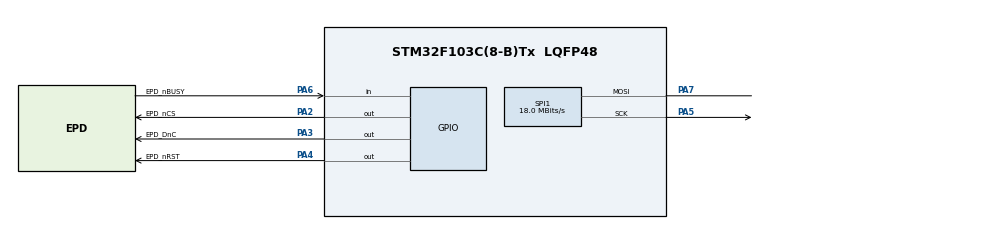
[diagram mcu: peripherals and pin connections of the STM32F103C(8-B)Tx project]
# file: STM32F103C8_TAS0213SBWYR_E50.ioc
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Mcu.Family=STM32F1
Mcu.Name=STM32F103C(8-B)Tx
Mcu.Package=LQFP48
NVIC.PriorityGroup=NVIC_PRIORITYGROUP_4
PA13.Mode=Serial_Wire
PA13.Signal=SYS_JTMS-SWDIO
PA14.Mode=Serial_Wire
PA14.Signal=SYS_JTCK-SWCLK
PA2.GPIO_Label=EPD_nCS
PA2.Signal=GPIO_Output
PA3.GPIO_Label=EPD_DnC
PA3.Signal=GPIO_Output
PA4.GPIO_Label=EPD_nRST
PA4.Signal=GPIO_Output
PA5.Mode=Simplex_Bidirectional_Master
PA5.Signal=SPI1_SCK
PA6.GPIO_Label=EPD_nBUSY
PA6.Signal=GPIO_Input
PA7.Mode=Simplex_Bidirectional_Master
PA7.Signal=SPI1_MOSI
PC14-OSC32_IN.Mode=LSE-External-Oscillator
PC14-OSC32_IN.Signal=RCC_OSC32_IN
PC15-OSC32_OUT.Mode=LSE-External-Oscillator
PC15-OSC32_OUT.Signal=RCC_OSC32_OUT
PD0-OSC_IN.Mode=HSE-External-Oscillator
PD0-OSC_IN.Signal=RCC_OSC_IN
PD1-OSC_OUT.Mode=HSE-External-Oscillator
PD1-OSC_OUT.Signal=RCC_OSC_OUT
ProjectManager.HeapSize=0x200
ProjectManager.StackSize=0x400
ProjectManager.TargetToolchain=CMake
RCC.AHBFreq_Value=72000000
RCC.APB1CLKDivider=RCC_HCLK_DIV2
RCC.APB1Freq_Value=36000000
RCC.APB1TimFreq_Value=72000000
RCC.APB2Freq_Value=72000000
RCC.APB2TimFreq_Value=72000000
RCC.HCLKFreq_Value=72000000
RCC.PLLMUL=RCC_PLL_MUL9
RCC.PLLSourceVirtual=RCC_PLLSOURCE_HSE
RCC.SYSCLKFreq_VALUE=72000000
RCC.SYSCLKSource=RCC_SYSCLKSOURCE_PLLCLK
RCC.USBFreq_Value=48000000
RCC.USBPrescaler=RCC_USBCLKSOURCE_PLL_DIV1_5
SPI1.BaudRatePrescaler=SPI_BAUDRATEPRESCALER_4
SPI1.CalculateBaudRate=18.0 MBits/s
SPI1.Direction=SPI_DIRECTION_1LINE
SPI1.Mode=SPI_MODE_MASTER
SPI1.VirtualType=VM_MASTER
board=custom

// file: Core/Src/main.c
/* USER CODE BEGIN Header */
/**
  ******************************************************************************
  * @file           : main.c
  * @brief          : Main program body
  ******************************************************************************
  * @attention
  *
  * Copyright (c) 2025 STMicroelectronics.
  * All rights reserved.
  *
  * This software is licensed under terms that can be found in the LICENSE file
  * in the root directory of this software component.
  * If no LICENSE file comes with this software, it is provided AS-IS.
  *
  ******************************************************************************
  */
/* USER CODE END Header */
#include "main.h"

/* USER CODE BEGIN Includes */
#include "epd_api.h"
// #include "modules/TAS0266SBW_T90.h"
#include "modules/TAS0266SBW_T90.h"
#include "hal/ports/hal_stm32.h"
#include <string.h>
#include <stdlib.h>

/* USER CODE END Includes */

SPI_HandleTypeDef hspi1;

/* USER CODE BEGIN PV */
EPD_Handle epd_handle1;
/* USER CODE END PV */

void SystemClock_Config(void);
static void MX_GPIO_Init(void);
static void MX_SPI1_Init(void);

int main(void)
{

  /* MCU Configuration--------------------------------------------------------*/

  /* Reset of all peripherals, Initializes the Flash interface and the Systick. */
  HAL_Init();

  /* Configure the system clock */
  SystemClock_Config();

  /* Initialize all configured peripherals */
  MX_GPIO_Init();
  MX_SPI1_Init();
  /* USER CODE BEGIN 2 */

  STM32_EPD_Config epd1 = {
      .hspi = &hspi1,
      .cs_port = EPD_nCS_GPIO_Port,
      .cs_pin = EPD_nCS_Pin,
      .dc_port = EPD_DnC_GPIO_Port,
      .dc_pin = EPD_DnC_Pin,
      .rst_port = EPD_nRST_GPIO_Port,
      .rst_pin = EPD_nRST_Pin,
      .busy_port = EPD_nBUSY_GPIO_Port,
      .busy_pin = EPD_nBUSY_Pin,
  };
  EPD_HAL hal1 = EPD_HAL_InitSTM32(&epd1);
  EPD_API_Init(&epd_handle1, &hal1, &EPD_PROFILE_TAS0266SBW_T90);
  uint8_t status = EPD_Init(&epd_handle1);
  uint8_t image_data[5624];
  memset(image_data, 0xF0, sizeof(image_data));
  status = EPD_WriteImage(&epd_handle1, (uint8_t*)image_data, 5624, 0);
  status = EPD_Update(&epd_handle1);

  /* USER CODE END 2 */

  /* Infinite loop */
  while (1)
  {

  }
}

void SystemClock_Config(void)
{
  RCC_OscInitTypeDef RCC_OscInitStruct = {0};
  RCC_ClkInitTypeDef RCC_ClkInitStruct = {0};

  /** Initializes the RCC Oscillators according to the specified parameters
  * in the RCC_OscInitTypeDef structure.
  */
  RCC_OscInitStruct.OscillatorType = RCC_OSCILLATORTYPE_HSE;
  RCC_OscInitStruct.HSEState = RCC_HSE_ON;
  RCC_OscInitStruct.HSEPredivValue = RCC_HSE_PREDIV_DIV1;
  RCC_OscInitStruct.HSIState = RCC_HSI_ON;
  RCC_OscInitStruct.PLL.PLLState = RCC_PLL_ON;
  RCC_OscInitStruct.PLL.PLLSource = RCC_PLLSOURCE_HSE;
  RCC_OscInitStruct.PLL.PLLMUL = RCC_PLL_MUL9;
  if (HAL_RCC_OscConfig(&RCC_OscInitStruct) != HAL_OK)
  {
    Error_Handler();
  }

  /** Initializes the CPU, AHB and APB buses clocks
  */
  RCC_ClkInitStruct.ClockType = RCC_CLOCKTYPE_HCLK|RCC_CLOCKTYPE_SYSCLK
                              |RCC_CLOCKTYPE_PCLK1|RCC_CLOCKTYPE_PCLK2;
  RCC_ClkInitStruct.SYSCLKSource = RCC_SYSCLKSOURCE_PLLCLK;
  RCC_ClkInitStruct.AHBCLKDivider = RCC_SYSCLK_DIV2;
  RCC_ClkInitStruct.APB1CLKDivider = RCC_HCLK_DIV1;
  RCC_ClkInitStruct.APB2CLKDivider = RCC_HCLK_DIV1;

  if (HAL_RCC_ClockConfig(&RCC_ClkInitStruct, FLASH_LATENCY_2) != HAL_OK)
  {
    Error_Handler();
  }
}

static void MX_SPI1_Init(void)
{

  /* SPI1 parameter configuration*/
  hspi1.Instance = SPI1;
  hspi1.Init.Mode = SPI_MODE_MASTER;
  hspi1.Init.Direction = SPI_DIRECTION_1LINE;
  hspi1.Init.DataSize = SPI_DATASIZE_8BIT;
  hspi1.Init.CLKPolarity = SPI_POLARITY_LOW;
  hspi1.Init.CLKPhase = SPI_PHASE_1EDGE;
  hspi1.Init.NSS = SPI_NSS_SOFT;
  hspi1.Init.BaudRatePrescaler = SPI_BAUDRATEPRESCALER_32;
  hspi1.Init.FirstBit = SPI_FIRSTBIT_MSB;
  hspi1.Init.TIMode = SPI_TIMODE_DISABLE;
  hspi1.Init.CRCCalculation = SPI_CRCCALCULATION_DISABLE;
  hspi1.Init.CRCPolynomial = 10;
  if (HAL_SPI_Init(&hspi1) != HAL_OK)
  {
    Error_Handler();
  }

}

static void MX_GPIO_Init(void)
{
  GPIO_InitTypeDef GPIO_InitStruct = {0};

  /* GPIO Ports Clock Enable */
  __HAL_RCC_GPIOC_CLK_ENABLE();
  __HAL_RCC_GPIOD_CLK_ENABLE();
  __HAL_RCC_GPIOA_CLK_ENABLE();

  /*Configure GPIO pin Output Level */
  HAL_GPIO_WritePin(GPIOA, EPD_nCS_Pin|EPD_DnC_Pin|EPD_nRST_Pin, GPIO_PIN_RESET);

  /*Configure GPIO pins : EPD_nCS_Pin EPD_DnC_Pin EPD_nRST_Pin */
  GPIO_InitStruct.Pin = EPD_nCS_Pin|EPD_DnC_Pin|EPD_nRST_Pin;
  GPIO_InitStruct.Mode = GPIO_MODE_OUTPUT_PP;
  GPIO_InitStruct.Pull = GPIO_NOPULL;
  GPIO_InitStruct.Speed = GPIO_SPEED_FREQ_LOW;
  HAL_GPIO_Init(GPIOA, &GPIO_InitStruct);

  /*Configure GPIO pin : EPD_nBUSY_Pin */
  GPIO_InitStruct.Pin = EPD_nBUSY_Pin;
  GPIO_InitStruct.Mode = GPIO_MODE_INPUT;
  GPIO_InitStruct.Pull = GPIO_NOPULL;
  HAL_GPIO_Init(EPD_nBUSY_GPIO_Port, &GPIO_InitStruct);

}

void Error_Handler(void)
{
  __disable_irq();
  while (1)
  {
  }
}
